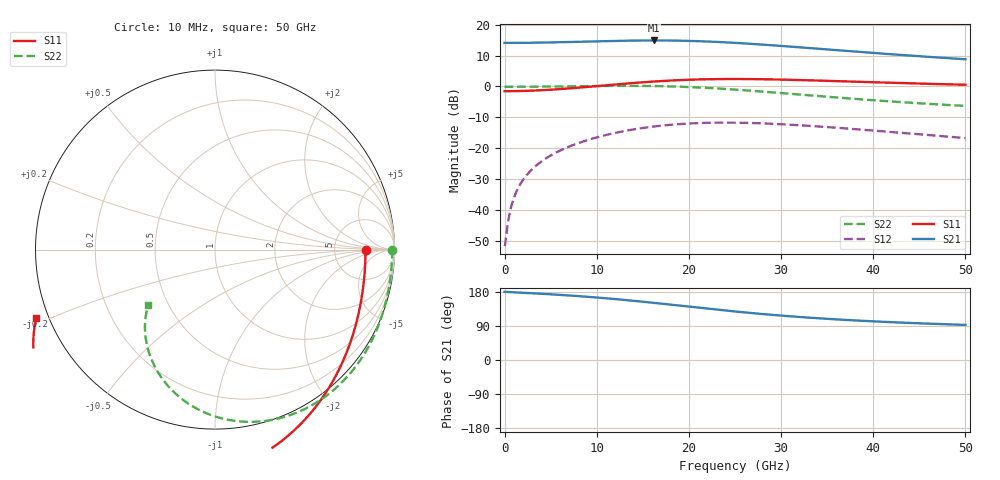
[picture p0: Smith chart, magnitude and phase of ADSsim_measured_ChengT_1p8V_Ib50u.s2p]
! Created Wed Apr 08 16:01:30 2026
# hz S ma R 50
! 2 Port Network Data from SP1.SP block
! freq  magS11  angS11  magS21  angS21  magS12  angS12  magS22  angS22
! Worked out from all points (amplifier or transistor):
!   1001 points, 10 MHz to 50 GHz, reference 50 ohm
!   highest |S21| = 14.9 dB at 16.26 GHz (marker M1)
!   |S21| within 3 dB of that: start of sweep to 35.46 GHz
!   unconditionally stable (mu >= 1): start of sweep to 83.36 MHz
!   at 8.308 GHz: K = -0.23, MSG = 16.2 dB, |S12| = -18.0 dB
!   at 25 GHz: K = -0.52, MSG = 12.9 dB, |S12| = -11.7 dB
!   at 50 GHz: K = -0.44, MSG = 12.7 dB, |S12| = -16.7 dB
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1e7  0.8387 -0.1  5.054 180.0  0.00263 3.3  0.9871 -0.0
5.5989e8  0.8393 -3.1  5.056 179.3  0.008981 71.2  0.9872 -2.0
9.0982e8  0.8403 -5.0  5.058 178.9  0.0142 76.4  0.9874 -3.3
1.45971e9  0.8429 -8.1  5.063 178.2  0.02254 78.6  0.988 -5.3
2.20956e9  0.8482 -12.2  5.073 177.2  0.03398 78.5  0.9891 -8.1
4.65907e9  0.8804 -25.5  5.133 173.9  0.07136 72.8  0.9958 -17.1
8.35833e9  0.9652 -44.8  5.283 168.0  0.1268 61.1  1.011 -31.2
1.265747e10  1.096 -65.9  5.469 159.4  0.1861 45.8  1.024 -48.4
1.45071e10  1.154 -74.5  5.521 155.0  0.2081 38.8  1.023 -56.0
1.625675e10  1.204 -82.5  5.538 150.7  0.2259 32.1  1.016 -63.2
1.670666e10  1.215 -84.5  5.537 149.5  0.23 30.3  1.013 -65.1
1.875625e10  1.262 -93.3  5.499 144.1  0.2454 22.5  0.9951 -73.5
2.105579e10  1.299 -102.6  5.391 138.0  0.2563 13.9  0.9641 -82.5
2.30054e10  1.316 -110.0  5.249 133.0  0.2604 6.9  0.9303 -89.8
2.5005e10  1.321 -116.9  5.066 128.0  0.2602 0.2  0.8905 -96.8
2.680464e10  1.316 -122.5  4.879 123.9  0.2569 -5.4  0.8521 -102.5
2.875425e10  1.303 -128.1  4.663 119.7  0.2507 -11.0  0.8096 -108.2
3.335333e10  1.254 -138.8  4.145 111.2  0.2295 -22.0  0.7134 -119.3
3.730254e10  1.204 -145.7  3.735 105.4  0.2085 -29.3  0.6416 -126.6
4.170166e10  1.151 -151.6  3.337 100.1  0.1853 -35.5  0.5754 -132.7
4.565087e10  1.107 -155.7  3.034 96.2  0.1659 -39.7  0.5274 -136.8
5e10  1.066 -159.1  2.752 92.6  0.1466 -42.9  0.4851 -140.1
